VERSION 5.7 ;
BUSBITCHARS "[]" ;
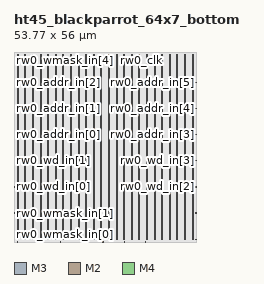
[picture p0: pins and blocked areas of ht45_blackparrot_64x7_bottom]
MACRO ht45_blackparrot_64x7_bottom
  FOREIGN ht45_blackparrot_64x7_bottom 0 0 ;
  SYMMETRY X Y R90 ;
  SIZE 53.770 BY 56.000 ;
  CLASS COVER ;
  PIN rw0_wmask_in[0]
    DIRECTION INPUT ;
    USE SIGNAL ;
    SHAPE ABUTMENT ;
    PORT
      LAYER M3 ;
      RECT 0.000 0.805 0.210 0.875 ;
    END
  END rw0_wmask_in[0]
  PIN rw0_wmask_in[1]
    DIRECTION INPUT ;
    USE SIGNAL ;
    SHAPE ABUTMENT ;
    PORT
      LAYER M3 ;
      RECT 0.000 8.505 0.210 8.575 ;
    END
  END rw0_wmask_in[1]
  PIN rw0_wmask_in[2]
    DIRECTION INPUT ;
    USE SIGNAL ;
    SHAPE ABUTMENT ;
    PORT
      LAYER M3 ;
      RECT 53.560 0.805 53.770 0.875 ;
    END
  END rw0_wmask_in[2]
  PIN rw0_wmask_in[3]
    DIRECTION INPUT ;
    USE SIGNAL ;
    SHAPE ABUTMENT ;
    PORT
      LAYER M3 ;
      RECT 53.560 8.505 53.770 8.575 ;
    END
  END rw0_wmask_in[3]
  PIN rw0_wmask_in[4]
    DIRECTION INPUT ;
    USE SIGNAL ;
    SHAPE ABUTMENT ;
    PORT
      LAYER M2 ;
      RECT 1.105 55.790 1.175 56.000 ;
    END
  END rw0_wmask_in[4]
  PIN rw0_wmask_in[5]
    DIRECTION INPUT ;
    USE SIGNAL ;
    SHAPE ABUTMENT ;
    PORT
      LAYER M2 ;
      RECT 5.665 55.790 5.735 56.000 ;
    END
  END rw0_wmask_in[5]
  PIN rw0_wmask_in[6]
    DIRECTION INPUT ;
    USE SIGNAL ;
    SHAPE ABUTMENT ;
    PORT
      LAYER M2 ;
      RECT 10.225 55.790 10.295 56.000 ;
    END
  END rw0_wmask_in[6]
  PIN rw0_wd_in[0]
    DIRECTION INPUT ;
    USE SIGNAL ;
    SHAPE ABUTMENT ;
    PORT
      LAYER M3 ;
      RECT 0.000 16.205 0.210 16.275 ;
    END
  END rw0_wd_in[0]
  PIN rw0_wd_in[1]
    DIRECTION INPUT ;
    USE SIGNAL ;
    SHAPE ABUTMENT ;
    PORT
      LAYER M3 ;
      RECT 0.000 23.905 0.210 23.975 ;
    END
  END rw0_wd_in[1]
  PIN rw0_wd_in[2]
    DIRECTION INPUT ;
    USE SIGNAL ;
    SHAPE ABUTMENT ;
    PORT
      LAYER M3 ;
      RECT 53.560 16.205 53.770 16.275 ;
    END
  END rw0_wd_in[2]
  PIN rw0_wd_in[3]
    DIRECTION INPUT ;
    USE SIGNAL ;
    SHAPE ABUTMENT ;
    PORT
      LAYER M3 ;
      RECT 53.560 23.905 53.770 23.975 ;
    END
  END rw0_wd_in[3]
  PIN rw0_wd_in[4]
    DIRECTION INPUT ;
    USE SIGNAL ;
    SHAPE ABUTMENT ;
    PORT
      LAYER M2 ;
      RECT 1.105 0.000 1.175 0.210 ;
    END
  END rw0_wd_in[4]
  PIN rw0_wd_in[5]
    DIRECTION INPUT ;
    USE SIGNAL ;
    SHAPE ABUTMENT ;
    PORT
      LAYER M2 ;
      RECT 7.375 0.000 7.445 0.210 ;
    END
  END rw0_wd_in[5]
  PIN rw0_wd_in[6]
    DIRECTION INPUT ;
    USE SIGNAL ;
    SHAPE ABUTMENT ;
    PORT
      LAYER M2 ;
      RECT 13.645 0.000 13.715 0.210 ;
    END
  END rw0_wd_in[6]
  PIN rw0_rd_out[0]
    DIRECTION OUTPUT ;
    USE SIGNAL ;
    SHAPE ABUTMENT ;
    PORT
      LAYER M2 ;
      RECT 19.915 0.000 19.985 0.210 ;
    END
  END rw0_rd_out[0]
  PIN rw0_rd_out[1]
    DIRECTION OUTPUT ;
    USE SIGNAL ;
    SHAPE ABUTMENT ;
    PORT
      LAYER M2 ;
      RECT 26.185 0.000 26.255 0.210 ;
    END
  END rw0_rd_out[1]
  PIN rw0_rd_out[2]
    DIRECTION OUTPUT ;
    USE SIGNAL ;
    SHAPE ABUTMENT ;
    PORT
      LAYER M2 ;
      RECT 32.455 0.000 32.525 0.210 ;
    END
  END rw0_rd_out[2]
  PIN rw0_rd_out[3]
    DIRECTION OUTPUT ;
    USE SIGNAL ;
    SHAPE ABUTMENT ;
    PORT
      LAYER M2 ;
      RECT 38.725 0.000 38.795 0.210 ;
    END
  END rw0_rd_out[3]
  PIN rw0_rd_out[4]
    DIRECTION OUTPUT ;
    USE SIGNAL ;
    SHAPE ABUTMENT ;
    PORT
      LAYER M2 ;
      RECT 14.785 55.790 14.855 56.000 ;
    END
  END rw0_rd_out[4]
  PIN rw0_rd_out[5]
    DIRECTION OUTPUT ;
    USE SIGNAL ;
    SHAPE ABUTMENT ;
    PORT
      LAYER M2 ;
      RECT 19.345 55.790 19.415 56.000 ;
    END
  END rw0_rd_out[5]
  PIN rw0_rd_out[6]
    DIRECTION OUTPUT ;
    USE SIGNAL ;
    SHAPE ABUTMENT ;
    PORT
      LAYER M2 ;
      RECT 23.905 55.790 23.975 56.000 ;
    END
  END rw0_rd_out[6]
  PIN rw0_addr_in[0]
    DIRECTION INPUT ;
    USE SIGNAL ;
    SHAPE ABUTMENT ;
    PORT
      LAYER M3 ;
      RECT 0.000 31.605 0.210 31.675 ;
    END
  END rw0_addr_in[0]
  PIN rw0_addr_in[1]
    DIRECTION INPUT ;
    USE SIGNAL ;
    SHAPE ABUTMENT ;
    PORT
      LAYER M3 ;
      RECT 0.000 39.305 0.210 39.375 ;
    END
  END rw0_addr_in[1]
  PIN rw0_addr_in[2]
    DIRECTION INPUT ;
    USE SIGNAL ;
    SHAPE ABUTMENT ;
    PORT
      LAYER M3 ;
      RECT 0.000 47.005 0.210 47.075 ;
    END
  END rw0_addr_in[2]
  PIN rw0_addr_in[3]
    DIRECTION INPUT ;
    USE SIGNAL ;
    SHAPE ABUTMENT ;
    PORT
      LAYER M3 ;
      RECT 53.560 31.605 53.770 31.675 ;
    END
  END rw0_addr_in[3]
  PIN rw0_addr_in[4]
    DIRECTION INPUT ;
    USE SIGNAL ;
    SHAPE ABUTMENT ;
    PORT
      LAYER M3 ;
      RECT 53.560 39.305 53.770 39.375 ;
    END
  END rw0_addr_in[4]
  PIN rw0_addr_in[5]
    DIRECTION INPUT ;
    USE SIGNAL ;
    SHAPE ABUTMENT ;
    PORT
      LAYER M3 ;
      RECT 53.560 47.005 53.770 47.075 ;
    END
  END rw0_addr_in[5]
  PIN rw0_we_in
    DIRECTION INPUT ;
    USE SIGNAL ;
    SHAPE ABUTMENT ;
    PORT
      LAYER M2 ;
      RECT 28.465 55.790 28.535 56.000 ;
    END
  END rw0_we_in
  PIN rw0_ce_in
    DIRECTION INPUT ;
    USE SIGNAL ;
    SHAPE ABUTMENT ;
    PORT
      LAYER M2 ;
      RECT 33.025 55.790 33.095 56.000 ;
    END
  END rw0_ce_in
  PIN rw0_clk
    DIRECTION INPUT ;
    USE SIGNAL ;
    SHAPE ABUTMENT ;
    PORT
      LAYER M2 ;
      RECT 37.585 55.790 37.655 56.000 ;
    END
  END rw0_clk
  PIN VSS
    DIRECTION INOUT ;
    USE GROUND ;
    PORT
      LAYER M4 ;
      RECT 1.000 0.840 1.280 55.160 ;
      RECT 3.240 0.840 3.520 55.160 ;
      RECT 5.480 0.840 5.760 55.160 ;
      RECT 7.720 0.840 8.000 55.160 ;
      RECT 9.960 0.840 10.240 55.160 ;
      RECT 12.200 0.840 12.480 55.160 ;
      RECT 14.440 0.840 14.720 55.160 ;
      RECT 16.680 0.840 16.960 55.160 ;
      RECT 18.920 0.840 19.200 55.160 ;
      RECT 21.160 0.840 21.440 55.160 ;
      RECT 23.400 0.840 23.680 55.160 ;
      RECT 25.640 0.840 25.920 55.160 ;
      RECT 27.880 0.840 28.160 55.160 ;
      RECT 30.120 0.840 30.400 55.160 ;
      RECT 32.360 0.840 32.640 55.160 ;
      RECT 34.600 0.840 34.880 55.160 ;
      RECT 36.840 0.840 37.120 55.160 ;
      RECT 39.080 0.840 39.360 55.160 ;
      RECT 41.320 0.840 41.600 55.160 ;
      RECT 43.560 0.840 43.840 55.160 ;
      RECT 45.800 0.840 46.080 55.160 ;
      RECT 48.040 0.840 48.320 55.160 ;
      RECT 50.280 0.840 50.560 55.160 ;
      RECT 52.520 0.840 52.800 55.160 ;
    END
  END VSS
  PIN VDD
    DIRECTION INOUT ;
    USE POWER ;
    PORT
      LAYER M4 ;
      RECT 1.000 0.840 1.280 55.160 ;
      RECT 3.240 0.840 3.520 55.160 ;
      RECT 5.480 0.840 5.760 55.160 ;
      RECT 7.720 0.840 8.000 55.160 ;
      RECT 9.960 0.840 10.240 55.160 ;
      RECT 12.200 0.840 12.480 55.160 ;
      RECT 14.440 0.840 14.720 55.160 ;
      RECT 16.680 0.840 16.960 55.160 ;
      RECT 18.920 0.840 19.200 55.160 ;
      RECT 21.160 0.840 21.440 55.160 ;
      RECT 23.400 0.840 23.680 55.160 ;
      RECT 25.640 0.840 25.920 55.160 ;
      RECT 27.880 0.840 28.160 55.160 ;
      RECT 30.120 0.840 30.400 55.160 ;
      RECT 32.360 0.840 32.640 55.160 ;
      RECT 34.600 0.840 34.880 55.160 ;
      RECT 36.840 0.840 37.120 55.160 ;
      RECT 39.080 0.840 39.360 55.160 ;
      RECT 41.320 0.840 41.600 55.160 ;
      RECT 43.560 0.840 43.840 55.160 ;
      RECT 45.800 0.840 46.080 55.160 ;
      RECT 48.040 0.840 48.320 55.160 ;
      RECT 50.280 0.840 50.560 55.160 ;
      RECT 52.520 0.840 52.800 55.160 ;
    END
  END VDD
  OBS
    LAYER M1 ;
    RECT 0 0 53.770 56.000 ;
    LAYER M2 ;
    RECT 0 0 53.770 56.000 ;
    LAYER M3 ;
    RECT 0 0 53.770 56.000 ;
    LAYER M4 ;
    RECT 0 0 53.770 56.000 ;
    LAYER OVERLAP ;
    RECT 0 0 53.770 56.000 ;
  END
END ht45_blackparrot_64x7_bottom

END LIBRARY
